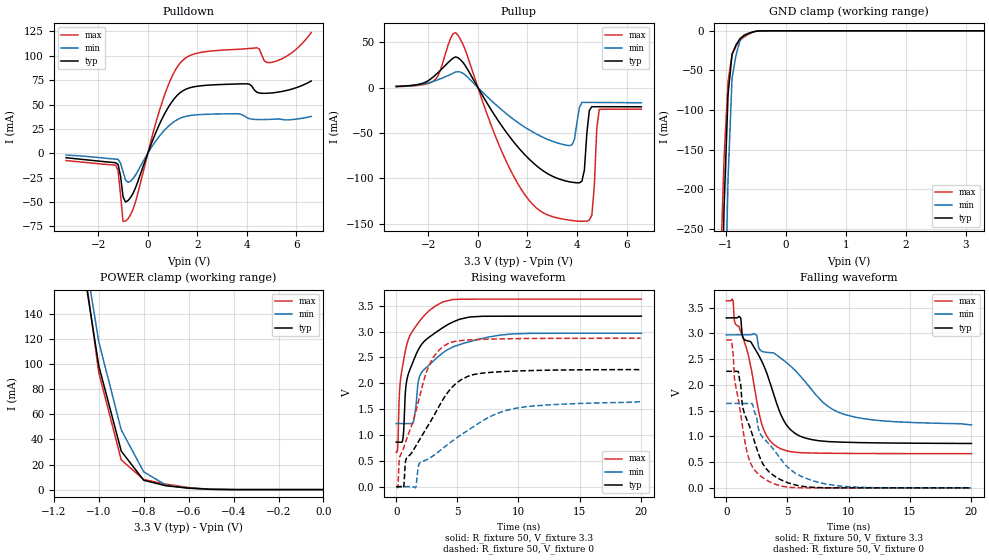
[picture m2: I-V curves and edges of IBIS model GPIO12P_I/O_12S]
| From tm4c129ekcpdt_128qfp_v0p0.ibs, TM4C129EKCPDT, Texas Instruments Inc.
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|   Model Cell GPIO12P_I/O_12S
[Model]   GPIO12P_I/O_12S
Model_type   I/O
Polarity   Non-Inverting
Enable   Active-Low
Vinl =  0.8
Vinh =  2
Cref =  15.0000pF
Rref =  100.0000M
Vref =  0V
Vmeas =  1.65
C_comp   6.029616p   5.226915p   6.778838p
[Model Spec]
Vinl   0.8   0.8   0.8
Vinh   2   2   2
[Temperature Range]   25   125   -40
[Voltage Range]   3.3   2.97   3.63
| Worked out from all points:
|   slope of the pulldown table from 0 to 0.495 V, typ, clamps not added: 15.9 ohm
|   slope of the pullup table from 0 to 0.495 V, typ, clamps not added: 21.8 ohm
|   GND clamp passes 1 mA (typ) near -0.53 V on its own axis
|   POWER clamp passes 1 mA (typ) near -0.58 V on its own axis
|   rising waveform, R_fixture 50, V_fixture 3.3: 20-80 % time 1.62ns typ, 2.38ns min, 1.22ns max; typ from 0.861 V to 3.3 V
|   rising waveform, R_fixture 50, V_fixture 0: 20-80 % time 3.44ns typ, 5.63ns min, 2.32ns max; typ from 0 V to 2.26 V
|   falling waveform, R_fixture 50, V_fixture 3.3: 20-80 % time 2.55ns typ, 4.55ns min, 1.71ns max; typ from 3.3 V to 0.861 V
|   falling waveform, R_fixture 50, V_fixture 0: 20-80 % time 1.79ns typ, 2.88ns min, 1.22ns max; typ from 2.26 V to 0 V
| Nom Voltages:
|   IBIASFET=3.3, VDDC=1.2, VDD=3.3, GND=0
| Min Voltages:
|   IBIASFET=2.97, VDDC=1.08, VDD=2.97, GND=0
| Max Voltages:
|   IBIASFET=3.63, VDDC=1.32, VDD=3.63, GND=0
[POWER_clamp]
|   voltage   I(typ)   I(min)   I(max)
-3.3V     3.668A     4.187A     4.057A
-1.067V   175.6mA    191.7mA    181.3mA
-1.033V   137.2mA    154.7mA    137.2mA
-1V       98.66mA    117.8mA    93.17mA
-900mV    30.66mA    47.6mA     23.68mA
-800mV    7.454mA    14.17mA    8.045mA
-700mV    3.021mA    3.466mA    4.326mA
-600mV    1.166mA    1.15mA     1.613mA
-500mV    219.7uA    295.1uA    245.5uA
0V        69.07pA    1.982nA    9.028pA
[Pulldown]
|   voltage   I(typ)   I(min)   I(max)
-3.3V     -4.531mA   -1.809mA   -7.41mA
-1.3V     -9.628mA   -6.013mA   -12.13mA
-1.2V     -11.53mA   -6.246mA   -17.7mA
-1V       -44.52mA   -18.9mA    -69.71mA
-900mV    -49.91mA   -27.35mA   -69.41mA
-500mV    -35.64mA   -22.45mA   -50.16mA
700mV     41.51mA    24.42mA    61.45mA
1.4V      63.88mA    36.91mA    95.09mA
4V        71.26mA    36.57mA    107.3mA
4.4V      62.7mA     34.65mA    108.2mA
5V        61.9mA     34.87mA    93.27mA
6.6V      74.13mA    37.78mA    123.8mA
[Pullup]
|   voltage   I(typ)   I(min)   I(max)
-3.3V     1.279mA    1.197mA    982.3uA
-1.7V     14.18mA    7.771mA    9.423mA
-900mV    33.79mA    17.11mA    60.55mA
1.8V      -71.23mA   -41.94mA   -114.2mA
3.7V      -103.8mA   -63.94mA   -146mA
4V        -104.9mA   -38.28mA   -147mA
4.3V      -90.74mA   -16.33mA   -147.2mA
4.5V      -25.16mA   -16.35mA   -145.8mA
4.6V      -21.1mA    -16.37mA   -140.6mA
4.8V      -21.09mA   -16.4mA    -44.84mA
4.9V      -21.08mA   -16.42mA   -23.95mA
6.6V      -21.2mA    -16.74mA   -23.82mA
[GND_clamp]
|   voltage   I(typ)   I(min)   I(max)
-3.3V     -18.01A    -17.27A    -18.6A
-1.1V     -459.9mA   -734.3mA   -318.7mA
-1.033V   -223.6mA   -411.6mA   -160.4mA
-966.7mV  -80.12mA   -186.8mA   -64.21mA
-900mV    -29.51mA   -59.8mA    -30.11mA
-833.3mV  -17.66mA   -30.4mA    -19.41mA
-766.7mV  -9.785mA   -12.28mA   -11.96mA
-700mV    -5.884mA   -5.445mA   -7.749mA
-500mV    -484.3uA   -573uA     -552.3uA
-366.7mV  -23.48uA   -48.41uA   -21.82uA
3.3V      69.07pA    6.412uA    7.794pA
[Ramp]
| variable   typ   min   max
dV/dt_f  1.4797726/2.597107n   1.0622157/5.2682284n   1.800002/1.7414415n
dV/dt_r   1.374826/3.4385264n  1.0039484/5.6322774n   1.737175/2.3302678n
R_load = 50
[Rising Waveform]
R_fixture = 50
V_fixture = 3.3
V_fixture_min = 2.97
V_fixture_max = 3.63
|   time   V(typ)   V(min)   V(max)
0s        861.5mV    1.221V     665.1mV
133.5ps   861.5mV    1.221V     789.8mV
287ps     861.5mV    1.221V     1.9V
540.8ps   911.8mV    1.221V     2.36V
854.7ps   2.045V     1.221V     2.741V
1.411ns   2.436V     1.253V     3.038V
1.973ns   2.717V     2.168V     3.223V
3.179ns   2.976V     2.462V     3.494V
8.501ns   3.3V       2.934V     3.63V
20.06ns   3.3V       2.97V      3.63V
[Rising Waveform]
R_fixture = 50
V_fixture = 0
V_fixture_min = 0
V_fixture_max = 0
|   time   V(typ)   V(min)   V(max)
0s        0V         0V         0V
605.1ps   -21.63mV   0V         749.9mV
794.2ps   522.1mV    0V         884.9mV
1.589ns   778.6mV    -19.76mV   1.441V
1.868ns   891.8mV    434.7mV    1.703V
2.54ns    1.156V     526mV      2.262V
3.947ns   1.733V     765.5mV    2.73V
5.846ns   2.134V     1.087V     2.838V
9.48ns    2.236V     1.503V     2.864V
20.01ns   2.264V     1.646V     2.872V
[Falling Waveform]
R_fixture = 50
V_fixture = 3.3
V_fixture_min = 2.97
V_fixture_max = 3.63
|   time   V(typ)   V(min)   V(max)
0s        3.3V       2.97V      3.63V
544.3ps   3.3V       2.97V      3.637V
688.4ps   3.3V       2.97V      3.22V
1.173ns   3.299V     2.97V      3.035V
1.371ns   2.914V     2.97V      2.909V
2.885ns   2.465V     2.653V     1.251V
4.118ns   1.639V     2.577V     801.1mV
5.644ns   1.053V     2.278V     691.5mV
9.522ns   886.7mV    1.437V     668.9mV
20.06ns   861.5mV    1.221V     664.2mV
[Falling Waveform]
R_fixture = 50
V_fixture = 0
V_fixture_min = 0
V_fixture_max = 0
|   time   V(typ)   V(min)   V(max)
0s        2.263V     1.64V      2.872V
439.5ps   2.263V     1.64V      2.863V
656.4ps   2.263V     1.64V      2.141V
999.3ps   2.24V      1.64V      1.699V
1.357ns   1.559V     1.64V      1.13V
1.812ns   1.249V     1.64V      587.8mV
3.079ns   433.1mV    955mV      179.7mV
5.204ns   86.32mV    360.3mV    10.01mV
7.434ns   6.532mV    113.4mV    0V
20.01ns   0V         0V         0V
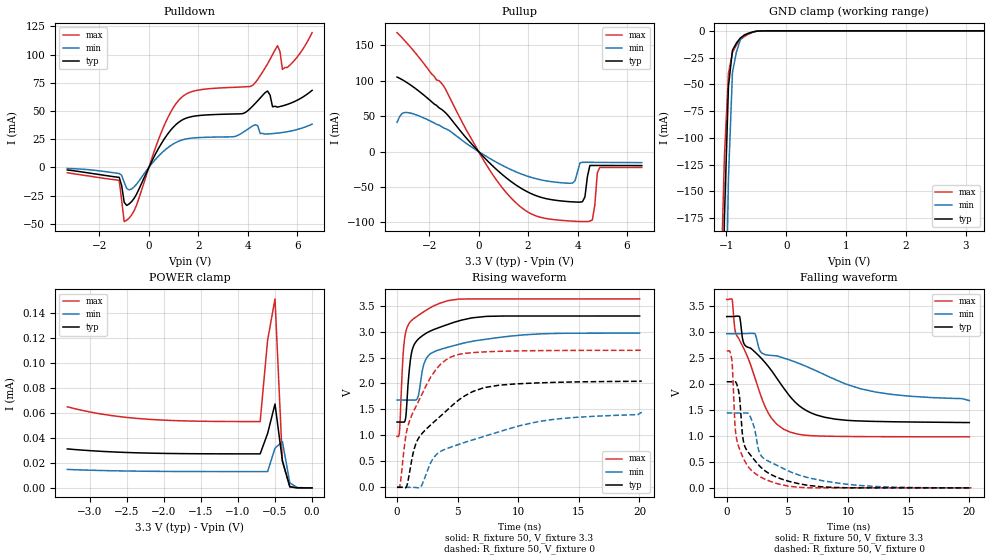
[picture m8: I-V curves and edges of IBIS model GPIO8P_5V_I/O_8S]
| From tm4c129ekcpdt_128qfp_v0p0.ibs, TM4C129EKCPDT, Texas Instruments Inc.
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|   Model Cell GPIO8P_5V_I/O_8S
[Model]   GPIO8P_5V_I/O_8S
Model_type   I/O
Polarity   Non-Inverting
Enable   Active-Low
Vinl =  0.8
Vinh =  2
Cref =  15.0000pF
Rref =  100.0000M
Vref =  0V
Vmeas =  1.65
C_comp   7.738177p   6.063161p   9.392973p
[Model Spec]
Vinl   0.8   0.8   0.8
Vinh   2   2   2
[Temperature Range]   25   125   -40
[Voltage Range]   3.3   2.97   3.63
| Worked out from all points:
|   slope of the pulldown table from 0 to 0.495 V, typ, clamps not added: 23.8 ohm
|   slope of the pullup table from 0 to 0.495 V, typ, clamps not added: 27.8 ohm
|   GND clamp passes 1 mA (typ) near -0.55 V on its own axis
|   rising waveform, R_fixture 50, V_fixture 3.3: 20-80 % time 1.11ns typ, 2.53ns min, 573ps max; typ from 1.26 V to 3.3 V
|   rising waveform, R_fixture 50, V_fixture 0: 20-80 % time 3.73ns typ, 7.25ns min, 2.27ns max; typ from 0 V to 2.04 V
|   falling waveform, R_fixture 50, V_fixture 3.3: 20-80 % time 4.29ns typ, 8.01ns min, 2.62ns max; typ from 3.3 V to 1.26 V
|   falling waveform, R_fixture 50, V_fixture 0: 20-80 % time 1.66ns typ, 3.19ns min, 947ps max; typ from 2.04 V to 0 V
| Nom Voltages:
|   VDDC=1.2, VDD=3.3, GND=0
| Min Voltages:
|   VDDC=1.08, VDD=2.97, GND=0
| Max Voltages:
|   VDDC=1.32, VDD=3.63, GND=0
[POWER_clamp]
|   voltage   I(typ)   I(min)   I(max)
-3.3V     31.22uA    14.77uA    64.95uA
-2.8V     29.13uA    13.84uA    58.77uA
-2.3V     27.98uA    13.34uA    55.36uA
-1.7V     27.4uA     13.1uA     53.62uA
-700mV    27.24uA    13.03uA    53.12uA
-600mV    43.52uA    13.03uA    118.2uA
-500mV    67.2uA     31.8uA     151.5uA
-400mV    21.58uA    37.04uA    21.1uA
-300mV    927.4nA    3.873uA    611.4nA
-200mV    28.93nA    266.5nA    11.51nA
0V        696.9pA    10.99nA    568.3pA
[Pulldown]
|   voltage   I(typ)   I(min)   I(max)
-3.3V     -2.325mA   -1.011mA   -4.829mA
-1.2V     -8.9mA     -5.443mA   -11.78mA
-1V       -30.94mA   -13.35mA   -48.07mA
-900mV    -33.77mA   -18.67mA   -46.9mA
-500mV    -23.82mA   -14.99mA   -33.55mA
600mV     24.46mA    14.43mA    36.18mA
1.3V      41.39mA    23.95mA    61.62mA
4.2V      54.39mA    36.75mA    72.77mA
4.8V      67.66mA    29.61mA    91.8mA
5.2V      53.41mA    30.34mA    107.8mA
5.4V      54.46mA    30.89mA    86.79mA
6.6V      68.25mA    38.26mA    119.5mA
[Pullup]
|   voltage   I(typ)   I(min)   I(max)
-3.3V     105mA      41.12mA    167.7mA
-2.4V     84.74mA    50.07mA    132.2mA
-1.4V     56.66mA    33.11mA    91.73mA
700mV     -24.56mA   -14.69mA   -39.08mA
2.1V      -58.93mA   -36.13mA   -87.33mA
3.8V      -70.97mA   -44.41mA   -98.09mA
4.2V      -70.71mA   -15.19mA   -98.64mA
4.5V      -19.61mA   -15.23mA   -98.06mA
4.6V      -19.61mA   -15.25mA   -96.39mA
4.8V      -19.61mA   -15.28mA   -30.07mA
4.9V      -19.62mA   -15.3mA    -22.42mA
6.6V      -19.78mA   -15.6mA    -22.44mA
[GND_clamp]
|   voltage   I(typ)   I(min)   I(max)
-3.3V     -16.36A    -15.34A    -17.18A
-1.1V     -382.1mA   -633.4mA   -250.1mA
-1.033V   -173.3mA   -336.5mA   -116.4mA
-966.7mV  -52.02mA   -138.4mA   -39.81mA
-900mV    -18.21mA   -38.98mA   -20.34mA
-833.3mV  -11.36mA   -19.82mA   -13.17mA
-766.7mV  -6.618mA   -8.051mA   -8.134mA
-700mV    -3.983mA   -3.675mA   -5.247mA
-500mV    -328.3uA   -388.2uA   -374.5uA
-366.7mV  -15.94uA   -32.84uA   -14.83uA
3.3V      696.9pA    8.348uA    426.1pA
[Ramp]
| variable   typ   min   max
dV/dt_f   1.231019/4.291597n  0.77759801/8.0026194n  1.5950638/2.6215481n
dV/dt_r  1.2345266/3.7273164n 0.87505534/7.2485224n  1.5897027/2.2683384n
R_load = 50
[Rising Waveform]
R_fixture = 50
V_fixture = 3.3
V_fixture_min = 2.97
V_fixture_max = 3.63
|   time   V(typ)   V(min)   V(max)
0s        1.258V     1.681V     981.8mV
205ps     1.258V     1.681V     1.072V
510.2ps   1.255V     1.681V     2.587V
756ps     1.432V     1.681V     3.025V
1.007ns   2.25V      1.681V     3.162V
1.263ns   2.656V     1.681V     3.229V
1.712ns   2.845V     1.729V     3.304V
2.63ns    2.998V     2.546V     3.445V
7.35ns    3.293V     2.854V     3.63V
20.01ns   3.3V       2.97V      3.63V
[Rising Waveform]
R_fixture = 50
V_fixture = 0
V_fixture_min = 0
V_fixture_max = 0
|   time   V(typ)   V(min)   V(max)
0s        0V         0V         0V
267.5ps   0V         0V         67.56mV
761ps     3.272mV    0V         1.036V
1.18ns    485.4mV    0V         1.371V
1.877ns   982.8mV    -2.631mV   1.706V
3.016ns   1.252V     568.3mV    2.205V
4.429ns   1.55V      773mV      2.509V
6.228ns   1.843V     911.8mV    2.595V
8.454ns   1.968V     1.071V     2.62V
20.2ns    2.045V     1.447V     2.639V
[Falling Waveform]
R_fixture = 50
V_fixture = 3.3
V_fixture_min = 2.97
V_fixture_max = 3.63
|   time   V(typ)   V(min)   V(max)
0s        3.3V       2.97V      3.63V
445.7ps   3.3V       2.97V      3.633V
682.7ps   3.303V     2.97V      3.043V
1.058ns   3.303V     2.97V      2.844V
1.451ns   2.765V     2.97V      2.664V
2.33ns    2.616V     2.969V     2.12V
3.17ns    2.413V     2.567V     1.563V
4.678ns   1.93V      2.503V     1.132V
8.058ns   1.361V     2.182V     996mV
20.01ns   1.258V     1.681V     982.8mV
[Falling Waveform]
R_fixture = 50
V_fixture = 0
V_fixture_min = 0
V_fixture_max = 0
|   time   V(typ)   V(min)   V(max)
0s        2.045V     1.443V     2.639V
428.3ps   2.045V     1.443V     2.452V
664.3ps   2.046V     1.443V     1.272V
883.4ps   1.957V     1.443V     872.3mV
1.047ns   1.771V     1.443V     753.5mV
1.435ns   840.3mV    1.443V     537.8mV
2.025ns   612.5mV    1.325V     339.3mV
2.769ns   406mV      644.8mV    211.6mV
8.836ns   8.044mV    101.4mV    0V
20.2ns    0V         0V         0V
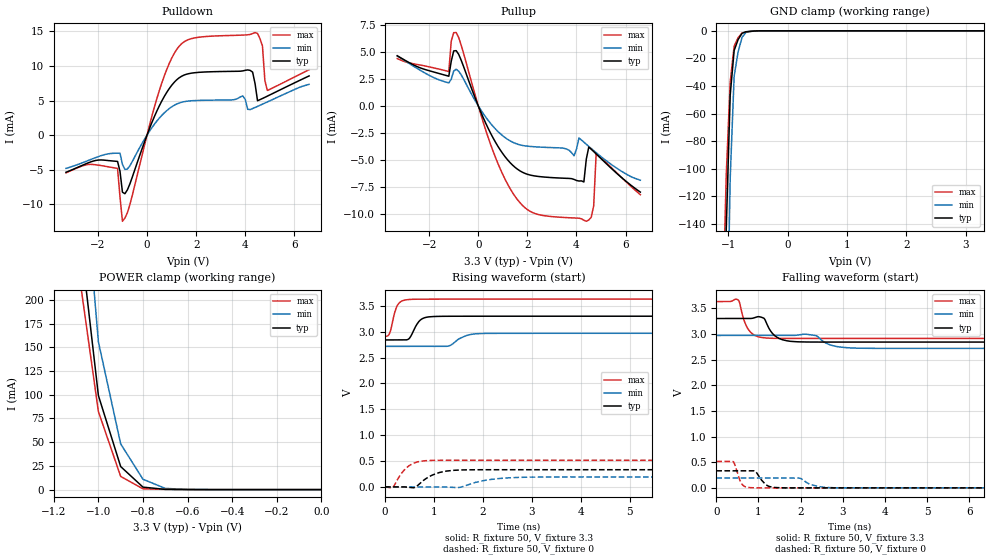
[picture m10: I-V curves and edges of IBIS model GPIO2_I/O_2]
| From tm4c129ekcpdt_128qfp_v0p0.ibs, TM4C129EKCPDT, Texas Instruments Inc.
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|   Model Cell GPIO2_I/O_2
[Model]   GPIO2_I/O_2
Model_type   I/O
Polarity   Non-Inverting
Enable   Active-Low
Vinl =  0.8
Vinh =  2
Cref =  15.0000pF
Rref =  100.0000M
Vref =  0V
Vmeas =  1.65
C_comp   3.906872p   3.211855p   4.659324p
[Model Spec]
Vinl   0.8   0.8   0.8
Vinh   2   2   2
[Temperature Range]   25   125   -40
[Voltage Range]   3.3   2.97   3.63
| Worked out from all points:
|   slope of the pulldown table from 0 to 0.495 V, typ, clamps not added: 118 ohm
|   slope of the pullup table from 0 to 0.495 V, typ, clamps not added: 198 ohm
|   GND clamp passes 1 mA (typ) near -0.72 V on its own axis
|   POWER clamp passes 1 mA (typ) near -0.73 V on its own axis
|   rising waveform, R_fixture 50, V_fixture 3.3: 20-80 % time 165ps typ, 260ps min, 118ps max; typ from 2.84 V to 3.3 V
|   rising waveform, R_fixture 50, V_fixture 0: 20-80 % time 359ps typ, 565ps min, 261ps max; typ from 0 V to 0.332 V
|   falling waveform, R_fixture 50, V_fixture 3.3: 20-80 % time 251ps typ, 338ps min, 202ps max; typ from 3.3 V to 2.84 V
|   falling waveform, R_fixture 50, V_fixture 0: 20-80 % time 193ps typ, 307ps min, 129ps max; typ from 0.332 V to 0 V
| Nom Voltages:
|   IBIASFET=3.3, VDDC=1.2, VDDA=3.3, VDD=3.3, GND=0, GNDA=0
| Min Voltages:
|   IBIASFET=2.97, VDDC=1.08, VDDA=2.97, VDD=2.97, GND=0, GNDA=0
| Max Voltages:
|   IBIASFET=3.63, VDDC=1.32, VDDA=3.63, VDD=3.63, GND=0, GNDA=0
[POWER_clamp]
|   voltage   I(typ)   I(min)   I(max)
-3.3V     12.79A     11.69A     13.85A
-1.1V     303.6mA    434.7mA    250.1mA
-1.067V   235.4mA    341.7mA    194.2mA
-1.033V   167.3mA    248.8mA    138.2mA
-1V       99.14mA    155.8mA    82.26mA
-900mV    24.28mA    48.16mA    13.88mA
-800mV    2.606mA    10.92mA    819.1uA
-700mV    259.6uA    1.276mA    245.1uA
-600mV    66.08uA    152.4uA    78.27uA
0V        4.099pA    261.1pA    -1.288pA
[Pulldown]
|   voltage   I(typ)   I(min)   I(max)
-3.3V     -5.378mA   -4.816mA   -5.461mA
-1.2V     -3.806mA   -2.612mA   -4.816mA
-1V       -8.265mA   -4.244mA   -12.47mA
700mV     5.566mA    3.205mA    8.526mA
1.7V      8.888mA    4.934mA    13.83mA
3.9V      9.287mA    5.668mA    14.47mA
4.2V      9.362mA    3.692mA    14.56mA
4.5V      4.968mA    4.151mA    14.7mA
4.7V      5.294mA    4.472mA    12.92mA
4.8V      5.463mA    4.635mA    7.89mA
4.9V      5.635mA    4.798mA    6.454mA
6.6V      8.559mA    7.346mA    9.467mA
[Pullup]
|   voltage   I(typ)   I(min)   I(max)
-3.3V     4.646mA    4.613mA    4.383mA
-1.2V     2.745mA    2.123mA    3.175mA
-1.1V     4.139mA    2.472mA    5.999mA
-900mV    5.116mA    3.394mA    6.792mA
800mV     -3.747mA   -2.376mA   -5.338mA
2.1V      -6.405mA   -3.759mA   -9.761mA
3.9V      -6.818mA   -4.624mA   -10.39mA
4.3V      -7.052mA   -3.363mA   -10.6mA
4.5V      -3.817mA   -3.758mA   -10.58mA
4.7V      -4.235mA   -4.149mA   -9.276mA
4.8V      -4.452mA   -4.34mA    -4.449mA
6.6V      -7.993mA   -6.889mA   -8.235mA
[GND_clamp]
|   voltage   I(typ)   I(min)   I(max)
-3.3V     -13.29A    -11.96A    -14.49A
-1.1V     -306.4mA   -502mA     -214mA
-1.033V   -144.1mA   -263.5mA   -104.9mA
-966.7mV  -46.75mA   -107.2mA   -37.22mA
-900mV    -14.24mA   -32.82mA   -11.06mA
-833.3mV  -6.32mA    -15.27mA   -4.953mA
-766.7mV  -1.798mA   -4.702mA   -1.537mA
-700mV    -674.7uA   -1.125mA   -814.2uA
-500mV    -34.63uA   -53.97uA   -31.22uA
3.3V      4.099pA    425.8nA    -4.281pA
[Ramp]
| variable   typ   min   max
dV/dt_f 0.29723109/0.25164659n 0.16674833/0.33932608n 0.45950538/0.20377875n
dV/dt_r 0.20971817/0.3634721n 0.12319155/0.57097451n 0.31986018/0.26335086n
R_load = 50
[Rising Waveform]
R_fixture = 50
V_fixture = 3.3
V_fixture_min = 2.97
V_fixture_max = 3.63
|   time   V(typ)   V(min)   V(max)
0s        2.841V     2.717V     2.912V
93.3ps    2.841V     2.717V     2.972V
199.6ps   2.841V     2.717V     3.38V
270.5ps   2.841V     2.717V     3.537V
523.4ps   2.908V     2.717V     3.626V
737.3ps   3.238V     2.717V     3.629V
1.067ns   3.297V     2.717V     3.63V
1.723ns   3.3V       2.942V     3.63V
2.051ns   3.3V       2.967V     3.63V
20.04ns   3.3V       2.97V      3.63V
[Rising Waveform]
R_fixture = 50
V_fixture = 0
V_fixture_min = 0
V_fixture_max = 0
|   time   V(typ)   V(min)   V(max)
0s        0V         0V         0V
160.3ps   0V         0V         -7.111mV
371.8ps   0V         0V         305.7mV
595.1ps   -14.49mV   0V         462.6mV
907.5ps   201.2mV    0V         511.3mV
1.377ns   319.3mV    -8.392mV   514.7mV
1.542ns   327.4mV    -6.437mV   514.6mV
2.169ns   332.3mV    145.1mV    514.3mV
2.96ns    332.2mV    188.8mV    514.2mV
20.01ns   332.2mV    192.5mV    514.3mV
[Falling Waveform]
R_fixture = 50
V_fixture = 3.3
V_fixture_min = 2.97
V_fixture_max = 3.63
|   time   V(typ)   V(min)   V(max)
0s        3.3V       2.97V      3.63V
503.5ps   3.3V       2.97V      3.668V
792.3ps   3.3V       2.97V      3.051V
1.129ns   3.304V     2.97V      2.924V
1.287ns   3.057V     2.97V      2.915V
1.759ns   2.855V     2.97V      2.912V
2.341ns   2.841V     2.971V     2.912V
2.709ns   2.841V     2.784V     2.912V
3.361ns   2.841V     2.721V     2.912V
20.04ns   2.841V     2.717V     2.912V
[Falling Waveform]
R_fixture = 50
V_fixture = 0
V_fixture_min = 0
V_fixture_max = 0
|   time   V(typ)   V(min)   V(max)
0s        332.2mV    192.5mV    514.3mV
402.3ps   332.2mV    192.5mV    509.1mV
601.7ps   332.2mV    192.5mV    78.58mV
882.4ps   333.4mV    192.5mV    0V
1.197ns   50.91mV    192.5mV    0V
1.556ns   0V         192.5mV    0V
1.96ns    0V         191.4mV    0V
2.3ns     0V         51.31mV    0V
2.899ns   0V         0V         0V
20.01ns   0V         0V         0V
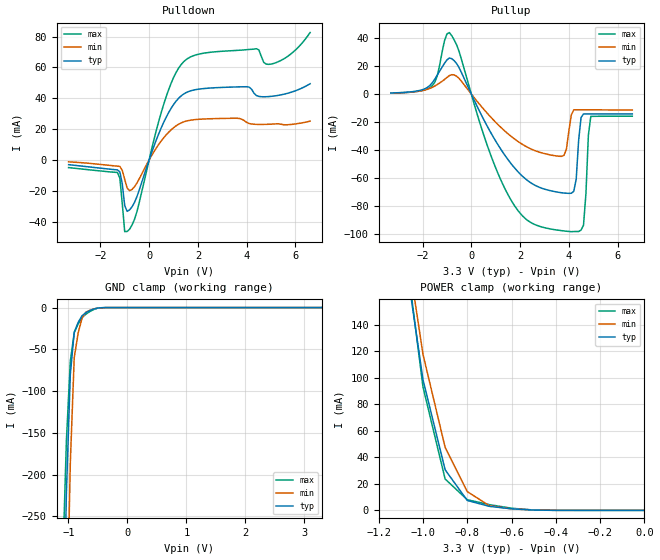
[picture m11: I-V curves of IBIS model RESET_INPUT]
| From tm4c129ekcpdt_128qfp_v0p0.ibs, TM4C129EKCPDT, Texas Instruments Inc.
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|   Model Cell RESET_INPUT
[Model]   RESET_INPUT
Model_type   Input
Polarity   Non-Inverting
Vinl =  0.8
Vinh =  2
C_comp   6.029616p   5.226915p   6.778838p
[Model Spec]
Vinl   0.8   0.8   0.8
Vinh   2   2   2
[Temperature Range]   25   125   -40
[Voltage Range]   3.3   2.97   3.63
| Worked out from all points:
|   slope of the pulldown table from 0 to 0.495 V, typ, clamps not added: 23.8 ohm
|   slope of the pullup table from 0 to 0.495 V, typ, clamps not added: 27.8 ohm
|   GND clamp passes 1 mA (typ) near -0.53 V on its own axis
|   POWER clamp passes 1 mA (typ) near -0.58 V on its own axis
| Nom Voltages:
|   IBIASFET=3.3, VDDC=1.2, VDD=3.3, GND=0
| Min Voltages:
|   IBIASFET=2.97, VDDC=1.08, VDD=2.97, GND=0
| Max Voltages:
|   IBIASFET=3.63, VDDC=1.32, VDD=3.63, GND=0
[POWER_clamp]
|   voltage   I(typ)   I(min)   I(max)
-3.3V     3.668A     4.187A     4.057A
-1.067V   175.6mA    191.7mA    181.3mA
-1.033V   137.2mA    154.7mA    137.2mA
-1V       98.66mA    117.8mA    93.17mA
-900mV    30.66mA    47.6mA     23.68mA
-800mV    7.454mA    14.17mA    8.045mA
-700mV    3.021mA    3.466mA    4.326mA
-600mV    1.166mA    1.15mA     1.613mA
-500mV    219.7uA    295.1uA    245.5uA
0V        69.07pA    1.982nA    9.028pA
[Pulldown]
|   voltage   I(typ)   I(min)   I(max)
-3.3V     -3.019mA   -1.206mA   -4.938mA
-1.3V     -6.416mA   -4.007mA   -8.087mA
-1.2V     -7.65mA    -4.163mA   -11.69mA
-1V       -29.59mA   -12.56mA   -46.46mA
-900mV    -33.29mA   -18.21mA   -46.32mA
-500mV    -23.81mA   -14.98mA   -33.54mA
700mV     27.72mA    16.29mA    41.06mA
1.4V      42.61mA    24.62mA    63.44mA
4V        47.51mA    24.37mA    71.53mA
4.4V      41.79mA    23.1mA     72.14mA
5V        41.27mA    23.24mA    62.2mA
6.6V      49.45mA    25.19mA    82.65mA
[Pullup]
|   voltage   I(typ)   I(min)   I(max)
-3.3V     716.3uA    635uA      605.7uA
-1.6V     8.021mA    4.755mA    5.925mA
-900mV    25.8mA     13.18mA    44.03mA
1.7V      -51.4mA    -31.27mA   -78.06mA
3.7V      -70.75mA   -44.67mA   -97.88mA
4V        -71.18mA   -26.4mA    -98.48mA
4.3V      -61.06mA   -11.3mA    -98.51mA
4.5V      -16.84mA   -11.31mA   -97.48mA
4.6V      -14.26mA   -11.32mA   -93.92mA
4.8V      -14.25mA   -11.33mA   -29.37mA
4.9V      -14.25mA   -11.34mA   -16.02mA
6.6V      -14.3mA    -11.49mA   -15.93mA
[GND_clamp]
|   voltage   I(typ)   I(min)   I(max)
-3.3V     -18.01A    -17.27A    -18.6A
-1.1V     -459.9mA   -734.3mA   -318.7mA
-1.033V   -223.6mA   -411.6mA   -160.4mA
-966.7mV  -80.12mA   -186.8mA   -64.21mA
-900mV    -29.51mA   -59.8mA    -30.11mA
-833.3mV  -17.66mA   -30.4mA    -19.41mA
-766.7mV  -9.785mA   -12.28mA   -11.96mA
-700mV    -5.884mA   -5.445mA   -7.749mA
-500mV    -484.3uA   -573uA     -552.3uA
-366.7mV  -23.48uA   -48.41uA   -21.82uA
3.3V      69.07pA    6.412uA    7.794pA
